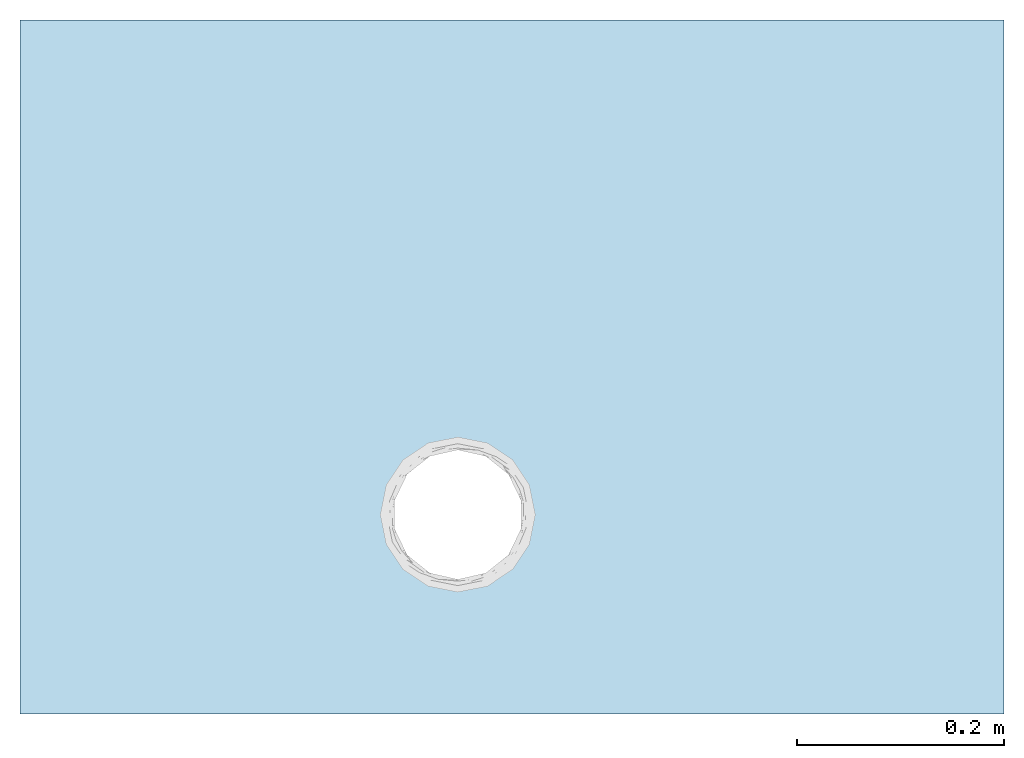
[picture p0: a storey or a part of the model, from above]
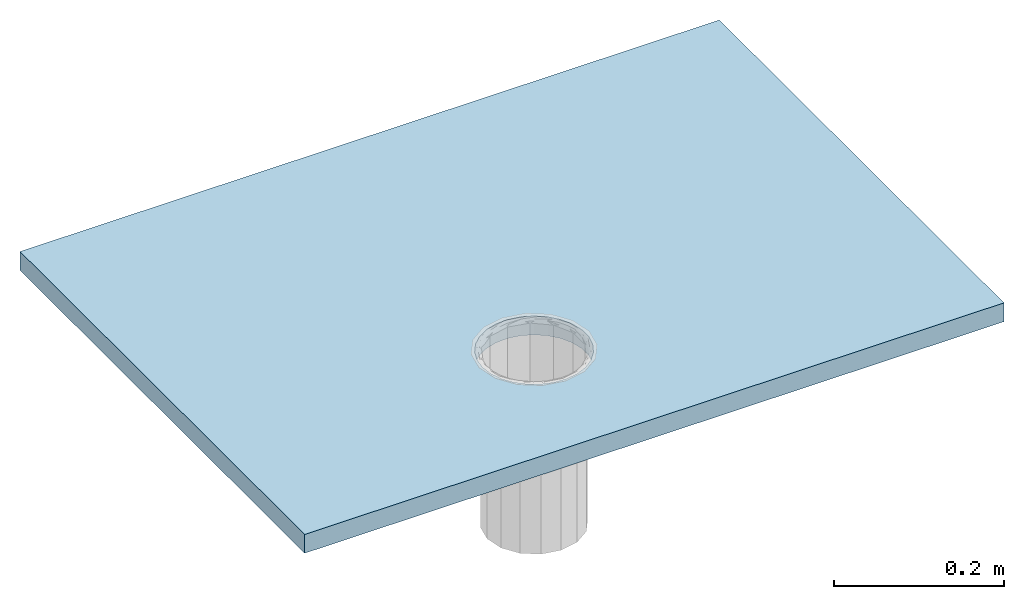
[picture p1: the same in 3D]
Properties of the parts of a building model (IFC2X3)

# File
Description: ViewDefinition [CoordinationView]
Time: 2016-10-03T14:31:03
Written by: The EXPRESS Data Manager Version 5.01.0100.02.64mod : 6 Jun 2012
Made in: 20140709_2115(x64) - Exporter 2014.0.2014.0709 - Default UI
Comment: STEP Physical File produced by: The EXPRESS Data Manager Version 5.01.0100.02.64mod : 6 Jun 2012 * Module: EDMstepFileFactory/EDMstandAlone * Creation date: Mon Oct 03 14:31:03 2016 * Host: BIM-HP * Database: C:\Users\dcole\AppData\Local\Temp\{88421420-18BD-407A-BA47-47F8B4370434}\ifc * Database version: 5507 * Database creation date: Mon Oct 03 14:31:01 2016 * Schema: IFC2X3 * Model: DataRepository.ifc * Model creation date: Mon Oct 03 14:31:02 2016 * Header model: DataRepository.ifc_HeaderModel * Header model creation date: Mon Oct 03 14:31:02 2016 * EDMuser: sdai-user * EDMgroup: sdai-group * License ID and type: 5605 : Permanent license. Expiry date: * EDMstepFileFactory options: 020000

# IfcProject
LongName: P:\Fastrack\53721_BELL-CHEM\ADDITIONAL DRAWINGS 2016 BIM\IFC\BC915.ifc

# IfcSite, Default
RefLatitude: 42, 24, 53, 508911; RefLongitude: -71, -15, -29, -58837; RefElevation: 0 mm

# IfcBuilding
Pset_BuildingCommon - NumberOfStoreys: 1

# IfcBuildingStorey, Level 1
LongName: Level 1; Elevation: 0 mm
Graphics - Line Pattern: -3000010; Line Weight: 1; Symbol at End 1 Default: no; Color: 0; Symbol at End 2 Default: yes
Dimensions - Computation Height: 0 mm
Identity Data - Structural: no; Building Story: yes; Name: Level 1
Constraints - Elevation: 0 mm; Elevation Base: Project Base Point

# IfcBuildingElementProxy: BC915 Dolphin Bin Ring, BC915:BC915 Dolphin Bin Ring:9751
In: Level 1
Material: Stainless Steel
Constraints - Moves With Nearby Elements: no; Host: Floor : Counter; Offset: -243.993 mm; Level: Level: Level 1
Dimensions - Volume: 0.000124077 m3; Width: 150mm diameter ring 125mm internal diameter; Height: 250mm
Phasing - Phase Created: New Construction
Pset_ManufacturerTypeInformation - Manufacturer: Dolphin Solutions Ltd.
Pset_BuildingElementProxyCommon - Reference: BC915 Dolphin Bin Ring
General - Product Page Link: https://www.dolphinsolutions.co.uk/product/bin-ring/; Product Data: Superior quality and timeless design for prestigious washrooms. High quality brushed stainless steel finish. High class welded seams for excellence in user experience. Unique extended depth to hide bin contents from easy visibility. Satin stainless steel.
Identity Data - Description: Bin ring; URL: www.dolphinsolutions.co.uk; Manufacturer: Dolphin Solutions Ltd.; Assembly Description: Other Plumbing Fixtures; Email: info@dolphinsolutions.co.uk; Fax No.: +44 (0) 1424 205 200; Address: Southpoint, Compass Park, Junction Road Bodiam, TN32 5BS; Assembly Code: D2010900; Tel No.: +44 (0) 1424 202 224; Model: BC915

# IfcOpeningElement: Opening
In: Level 1
Dimensions - Perimeter: 3240 mm; Area: 0.621109 m2; Thickness: 27 mm; Volume: 0.0167699 m3
Constraints - Level: Level: Level 1; Room Bounding: yes; Height Offset From Level: 0 mm; Related to Mass: no
Structural - Structural: no; Enable Analytical Model: no
Phasing - Phase Created: New Construction
Analytical Properties - Absorptance: 0.1; Roughness: 1
Graphics - Coarse Scale Fill Pattern: Solid fill; Coarse Scale Fill Color: 8454143
Construction - Default Thickness: 27 mm

# IfcSlab: Floor:Counter, Floor:Counter:2279
In: Level 1
PredefinedType: FLOOR; Material: Analytical Floor Surface 27 mm
Dimensions - Perimeter: 3240 mm; Area: 0.621109 m2; Thickness: 27 mm; Volume: 0.0167699 m3
Constraints - Level: Level: Level 1; Room Bounding: yes; Height Offset From Level: 0 mm; Related to Mass: no
Structural - Structural: no; Enable Analytical Model: no
Phasing - Phase Created: New Construction
Pset_SlabCommon - Reference: Counter; IsExternal: no; LoadBearing: yes
Analytical Properties - Absorptance: 0.1; Roughness: 1
Graphics - Coarse Scale Fill Pattern: Solid fill; Coarse Scale Fill Color: 8454143
Construction - Default Thickness: 27 mm
